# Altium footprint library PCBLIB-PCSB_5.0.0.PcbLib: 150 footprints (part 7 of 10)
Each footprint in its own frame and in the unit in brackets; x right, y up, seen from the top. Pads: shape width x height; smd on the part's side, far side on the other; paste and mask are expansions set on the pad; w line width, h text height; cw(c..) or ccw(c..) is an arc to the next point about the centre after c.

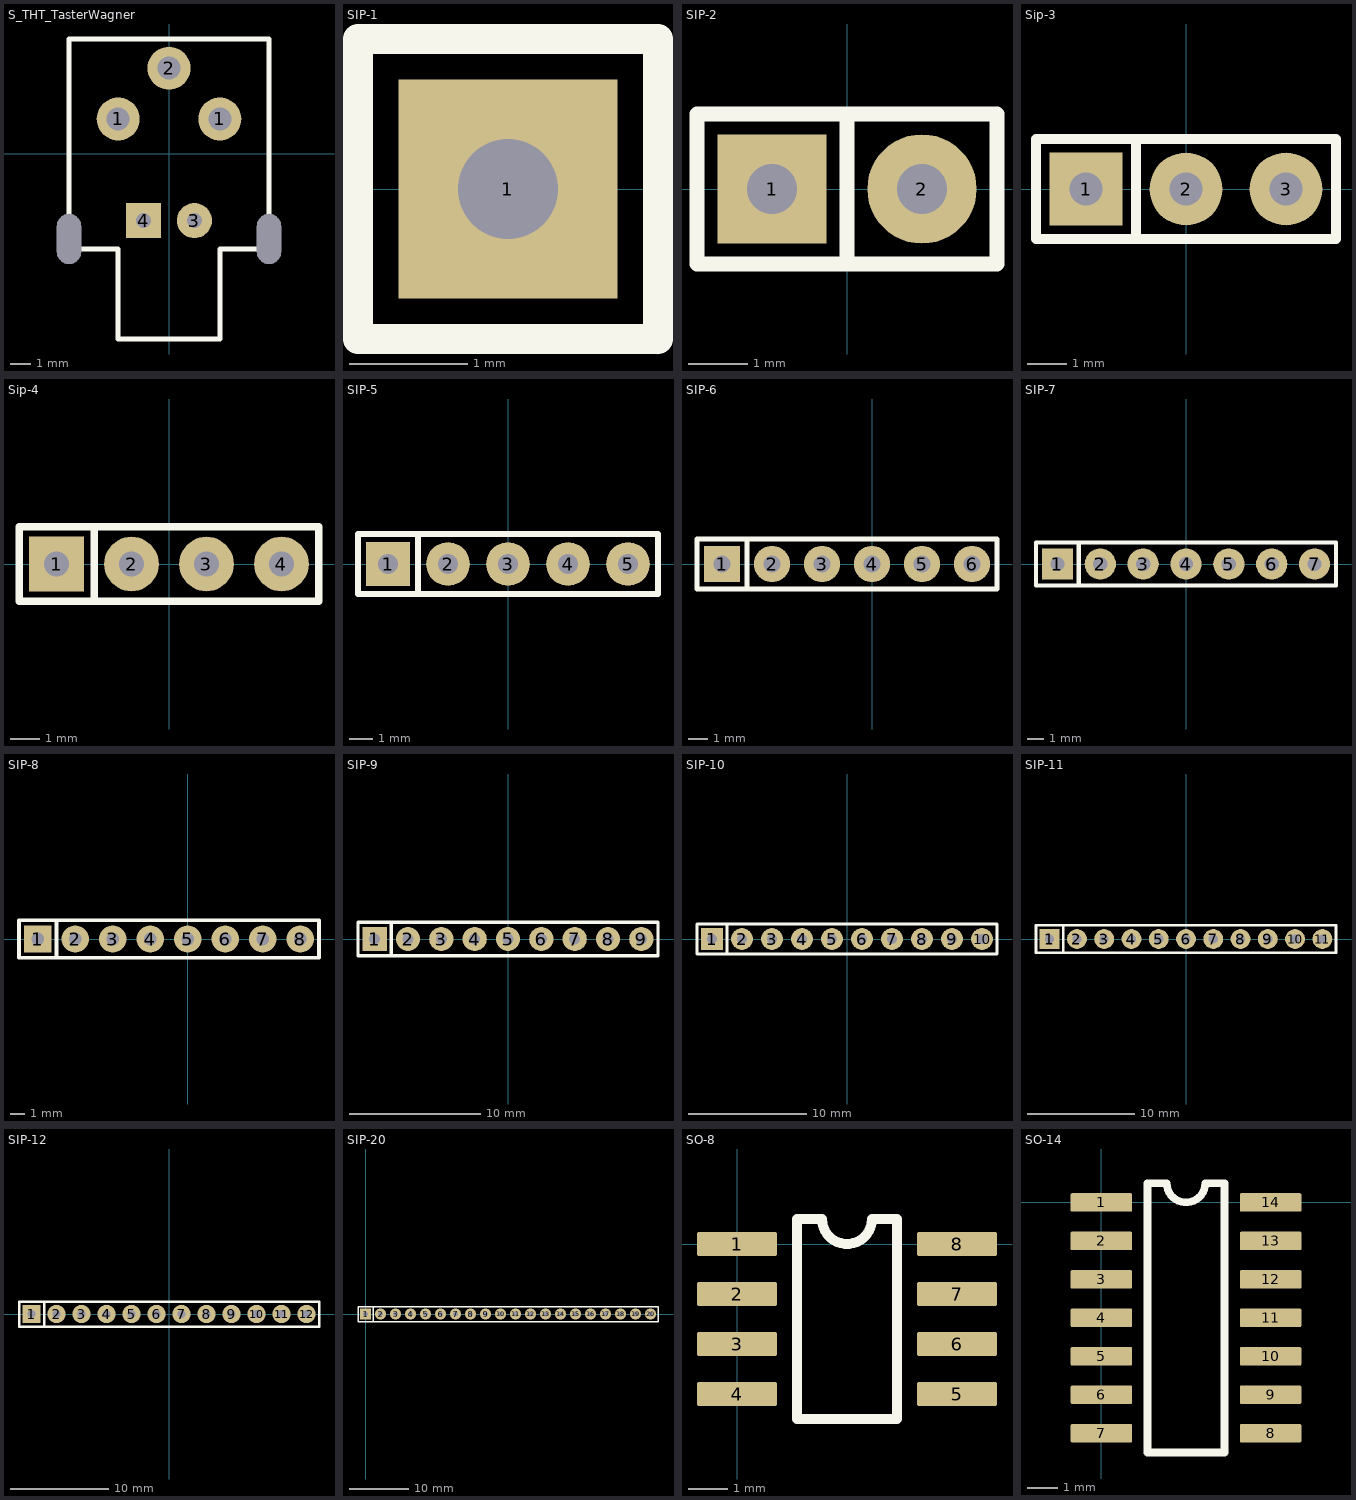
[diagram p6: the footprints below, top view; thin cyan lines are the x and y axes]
## S_THT_TasterWagner [mm] "LB-2024-04-17"
pads (7):
  round 2.15 hole 1.15: 1(-2.54,1.73) 1(2.54,1.73) 2(0,4.27)
  round 1.75 hole 0.75: 3(1.27,-3.35)
  rect 1.75x1.75 hole 0.75: 4(-1.27,-3.35)
  round 0.1 hole 1.2 slot 2.5 at 90 deg: H1(-5,-4.27) H2(5,-4.27)
Top Overlay:
  lines w0.254: -5,-4.77 -2.54,-4.77 -2.54,-9.27 1.065,-9.27 2.54,-9.27 2.54,-4.77 5,-4.77 5,5.73 -5,5.73 -5,-4.77

## SIP-1 [mm] "LB-2024-04-17"
pads (1):
  rect 1.85x1.85 hole 0.85: 1(-1.27,0)
Top Overlay:
  lines w0.254: -2.54,-1.27 0,-1.27 0,1.27 -2.54,1.27 -2.54,-1.27

## SIP-2 [mm] "LB-2024-04-17"
pads (2):
  rect 1.85x1.85 hole 0.85: 1(-1.27,0)
  round 1.85 hole 0.85: 2(1.27,0)
Top Overlay:
  lines w0.254: 0,-1.27 0,1.27 ; -2.54,-1.27 2.54,-1.27 2.54,1.27 -2.54,1.27 -2.54,-1.27

## Sip-3 [mm] "LB-2024-04-17"
pads (3):
  rect 1.85x1.85 hole 0.85: 1(-2.54,0)
  round 1.85 hole 0.85: 2(0,0) 3(2.54,0)
Top Overlay:
  lines w0.254: -1.27,-1.27 -1.27,1.27 ; -3.81,-1.27 -3.81,1.27 3.81,1.27 3.81,-1.27 -3.81,-1.27

## Sip-4 [mm] "LB-2024-04-17"
pads (4):
  rect 1.85x1.85 hole 0.85: 1(-3.81,0)
  round 1.85 hole 0.85: 2(-1.27,0) 3(1.27,0) 4(3.81,0)
Top Overlay:
  lines w0.254: -2.54,-1.27 -2.54,1.27 ; -5.08,-1.27 5.08,-1.27 5.08,1.27 -5.08,1.27 -5.08,-1.27

## SIP-5 [mm] "LB-2024-04-17"
pads (5):
  rect 1.85x1.85 hole 0.85: 1(-5.08,0)
  round 1.85 hole 0.85: 2(-2.54,0) 3(0,0) 4(2.54,0) 5(5.08,0)
Top Overlay:
  lines w0.254: -3.81,-1.27 -3.81,1.27 ; -6.35,-1.27 6.35,-1.27 6.35,1.27 -6.35,1.27 -6.35,-1.27

## SIP-6 [mm] "LB-2024-04-17"
pads (6):
  rect 1.85x1.85 hole 0.85: 1(-7.62,0)
  round 1.85 hole 0.85: 2(-5.08,0) 3(-2.54,0) 4(0,0) 5(2.54,0) 6(5.08,0)
Top Overlay:
  lines w0.254: -6.35,-1.27 -6.35,1.27 ; -8.89,-1.27 -8.89,1.27 6.35,1.27 6.35,-1.27 -8.89,-1.27

## SIP-7 [mm] "LB-2024-04-17"
pads (7):
  rect 1.85x1.85 hole 0.85: 1(-7.62,0)
  round 1.85 hole 0.85: 2(-5.08,0) 3(-2.54,0) 4(0,0) 5(2.54,0) 6(5.08,0) 7(7.62,0)
Top Overlay:
  lines w0.254: -6.35,-1.27 -6.35,1.27 ; -8.89,-1.27 8.89,-1.27 8.89,1.27 -8.89,1.27 -8.89,-1.27

## SIP-8 [mm] "LB-2024-04-17"
pads (8):
  rect 1.85x1.85 hole 0.85: 1(-10.16,0)
  round 1.85 hole 0.85: 2(-7.62,0) 3(-5.08,0) 4(-2.54,0) 5(0,0) 6(2.54,0) 7(5.08,0) 8(7.62,0)
Top Overlay:
  lines w0.254: -8.89,-1.27 -8.89,1.27 ; -11.43,-1.27 -11.43,1.27 8.89,1.27 8.89,-1.27 -11.43,-1.27

## SIP-9 [mm] "LB-2024-04-17"
pads (9):
  rect 1.85x1.85 hole 0.85: 1(-10.16,0)
  round 1.85 hole 0.85: 2(-7.62,0) 3(-5.08,0) 4(-2.54,0) 5(0,0) 6(2.54,0) 7(5.08,0) 8(7.62,0) 9(10.16,0)
Top Overlay:
  lines w0.254: -8.89,-1.27 -8.89,1.27 ; -11.43,-1.27 11.43,-1.27 11.43,1.27 -11.43,1.27 -11.43,-1.27

## SIP-10 [mm] "LB-2024-04-17"
pads (10):
  rect 1.85x1.85 hole 0.85: 1(-11.43,0)
  round 1.85 hole 0.85: 2(-8.89,0) 3(-6.35,0) 4(-3.81,0) 5(-1.27,0) 6(1.27,0) 7(3.81,0) 8(6.35,0) 9(8.89,0) 10(11.43,0)
Top Overlay:
  lines w0.254: -10.16,-1.27 -10.16,1.27 ; -12.7,-1.27 12.7,-1.27 12.7,1.27 -12.7,1.27 -12.7,-1.27

## SIP-11 [mm] "LB-2024-04-17"
pads (11):
  rect 1.85x1.85 hole 0.85: 1(-12.7,0)
  round 1.85 hole 0.85: 2(-10.16,0) 3(-7.62,0) 4(-5.08,0) 5(-2.54,0) 6(0,0) 7(2.54,0) 8(5.08,0) 9(7.62,0) 10(10.16,0) 11(12.7,0)
Top Overlay:
  lines w0.254: -11.43,-1.27 -11.43,1.27 ; -13.97,-1.27 -13.97,1.27 13.97,1.27 13.97,-1.27 -13.97,-1.27

## SIP-12 [mm] "LB-2024-04-17"
pads (12):
  rect 1.85x1.85 hole 0.85: 1(-13.97,0)
  round 1.85 hole 0.85: 2(-11.43,0) 3(-8.89,0) 4(-6.35,0) 5(-3.81,0) 6(-1.27,0) 7(1.27,0) 8(3.81,0) 9(6.35,0) 10(8.89,0) 11(11.43,0) 12(13.97,0)
Top Overlay:
  lines w0.254: -12.7,-1.27 -12.7,1.27 ; -15.24,-1.27 -15.24,1.27 15.24,1.27 15.24,-1.27 -15.24,-1.27

## SIP-20 [mm] "LB-2024-04-17"
pads (20):
  rect 1.85x1.85 hole 0.85: 1(0,0)
  round 1.85 hole 0.85: 2(2.54,0) 3(5.08,0) 4(7.62,0) 5(10.16,0) 6(12.7,0) 7(15.24,0) 8(17.78,0) 9(20.32,0) 10(22.86,0) 11(25.4,0) 12(27.94,0) 13(30.48,0) 14(33.02,0) 15(35.56,0) 16(38.1,0) 17(40.64,0) 18(43.18,0) 19(45.72,0) 20(48.26,0)
Top Overlay:
  lines w0.254: 1.27,-1.27 1.27,1.27 ; -1.27,-1.27 -1.27,1.27 49.53,1.27 49.53,-1.27 -1.27,-1.27

## SO-8 [mil] "LB-2024-04-17"
pads (8):
  rrect15% 80x24 smd paste-0.79 mask+1.97: 1(0,0) 2(0,-50) 3(0,-100) 4(0,-150) 5(220,-150) 6(220,-100) 7(220,-50) 8(220,0)
Top Overlay:
  lines w10: 60,-175 160,-175 160,25 135,25 cw(c110,25) 85,25 60,25 60,-175

## SO-14 [mil] "LB-2024-04-17"
pads (14):
  rrect15% 80x24 smd paste-0.79 mask+1.97: 1(0,0) 2(0,-50) 3(0,-100) 4(0,-150) 5(0,-200) 6(0,-250) 7(0,-300) 8(220,-300) 9(220,-250) 10(220,-200) 11(220,-150) 12(220,-100) 13(220,-50) 14(220,0)
Top Overlay:
  lines w10: 60,-325 160,-325 160,25 135,25 cw(c110,25) 85,25 60,25 60,-325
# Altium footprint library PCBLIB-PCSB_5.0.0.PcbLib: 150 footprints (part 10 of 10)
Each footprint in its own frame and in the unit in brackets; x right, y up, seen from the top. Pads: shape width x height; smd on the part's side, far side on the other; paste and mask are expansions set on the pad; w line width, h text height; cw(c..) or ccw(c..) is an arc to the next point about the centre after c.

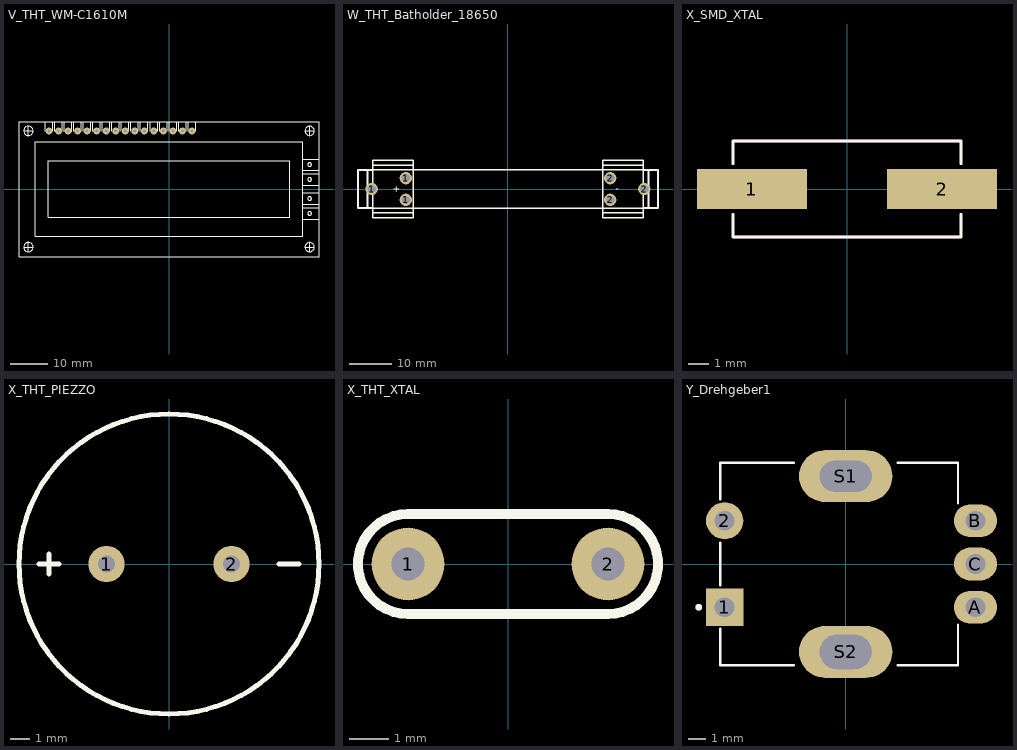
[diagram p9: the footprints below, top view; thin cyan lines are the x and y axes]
## V_THT_WM-C1610M [mm] "LB-2024-04-19"
pads (16):
  round 1.85 hole 0.85: 1(-32,15.5) 2(-29.46,15.5) 3(-26.92,15.5) 4(-24.38,15.5) 5(-21.84,15.5) 6(-19.3,15.5) 7(-16.76,15.5) 8(-14.22,15.5) 9(-11.68,15.5) 10(-9.14,15.5) 11(-6.6,15.5) 12(-4.06,15.5) 13(-1.52,15.5) 14(1.02,15.5) 15(3.56,15.5) 16(6.1,15.5)
Top Overlay:
  circle w0.2: c-37.51,15.538 r1.25
  circle w0.2: c-37.51,-15.462 r1.25
  circle w0.2: c37.49,15.538 r1.25
  circle w0.2: c37.49,6.538 r0.5
  circle w0.2: c37.49,2.578 r0.5
  circle w0.2: c37.49,-2.502 r0.5
  circle w0.2: c37.49,-6.462 r0.5
  circle w0.2: c37.49,-15.462 r1.25
  lines w0.1: -38.75,-15.462 -36.26,-15.462 ; -38.75,15.538 -36.26,15.538 ; -37.51,-16.75 -37.51,-14.25 ; -37.51,14.25 -37.51,16.75 ; 36.25,-15.462 38.74,-15.462 ; 36.25,15.538 38.74,15.538 ; 37.49,-16.75 37.49,-14.25 ; 37.49,14.25 37.49,16.75
  lines w0.2: -33.01,15.498 -33.01,18.038 ; -31.01,15.498 -31.01,18.038 ; -30.47,15.498 -30.47,18.038 ; -28.47,15.498 -28.47,18.038 ; -27.93,15.338 -27.93,18.038 ; -25.93,15.338 -25.93,18.038 ; -25.39,15.498 -25.39,18.038 ; -23.39,15.498 -23.39,18.038 ; -22.85,15.498 -22.85,18.038 ; -20.85,15.498 -20.85,18.038 ; -20.31,15.498 -20.31,18.038 ; -18.31,15.498 -18.31,18.038 ; -17.77,15.498 -17.77,18.038 ; -15.77,15.498 -15.77,18.038 ; -15.23,15.498 -15.23,18.038 ; -13.23,15.498 -13.23,18.038 ; -12.69,15.498 -12.69,18.038 ; -10.69,15.498 -10.69,18.038 ; -10.15,15.468 -10.15,18.038 ; -8.15,15.468 -8.15,18.038 ; -7.61,15.468 -7.61,18.038 ; -5.61,15.468 -5.61,18.038 ; -5.07,15.498 -5.07,18.038 ; -3.07,15.498 -3.07,18.038 ; -2.53,15.498 -2.53,18.038 ; -0.53,15.498 -0.53,18.038 ; 0.01,15.498 0.01,18.038 ; 2.01,15.498 2.01,18.038 ; 2.55,15.498 2.55,18.038 ; 4.55,15.498 4.55,18.038 ; 5.09,15.498 5.09,18.038 ; 7.09,15.498 7.09,18.038 ; 35.59,-7.962 39.99,-7.962 ; 35.59,-4.962 39.99,-4.962 ; 35.59,-4.002 39.99,-4.002 ; 35.59,-1.002 39.99,-1.002 ; 35.59,1.078 39.99,1.078 ; 35.59,4.078 39.99,4.078 ; 35.59,5.038 39.99,5.038 ; 35.59,8.038 39.99,8.038 ; -40.01,-17.962 39.99,-17.962 39.99,18.038 -40.01,18.038 -40.01,-17.962 ; -35.61,-12.562 -35.61,12.638 35.59,12.638 35.59,-12.562 -35.61,-12.562 ; -32.24,-7.462 32.22,-7.462 32.22,7.538 -32.24,7.538 -32.24,-7.462

## W_THT_Batholder_18650 [mm] "LB-2024-04-25"
height 17
pads (6):
  round 2.9 hole 1.9: 1(-32,0) 1(-24,-2.54) 1(-24,2.54) 2(24.006,-2.54) 2(24.006,2.54) 2(32,0)
Top Overlay:
  lines w0.4: -31.74,-6.75 -22.27,-6.75 ; -31.74,-6.71 -31.74,-5.552 -29.08,-5.552 -22.272,-5.552 ; -31.74,-5.492 -31.74,5.552 ; -31.74,-4.45 -35.22,-4.45 -35.22,4.45 -31.74,4.45 ; -31.74,6.71 -31.74,5.552 ; -31.74,6.75 -22.27,6.75 ; -22.272,5.552 -29.08,5.552 -31.74,5.552 ; -22.22,-6.75 -22.22,-5.552 -22.22,5.552 -22.22,6.75 ; 22.226,-6.75 22.226,-5.552 22.226,5.552 22.226,6.75 ; 22.276,-6.75 31.746,-6.75 ; 22.276,6.75 31.746,6.75 ; 22.278,-5.552 29.086,-5.552 31.746,-5.552 ; 22.278,5.552 29.086,5.552 31.746,5.552 31.746,6.71 ; 31.746,-6.71 31.746,-5.552 ; 31.746,-4.45 35.226,-4.45 35.226,4.45 31.746,4.45 ; 31.746,5.492 31.746,-5.552 ; -33,-4.5 33,-4.5 33,0 33,4.5 -33,4.5 -33,0 -33,-4.5
  text "+" at -25.3,0.7 h1.52
  text "-" at 25.3,-0.7 h1.52

## X_SMD_XTAL [mm] "LB-2024-04-17"
pads (2):
  rect 5.5x2 smd: 1(-4.75,0) 2(4.75,0)
Top Overlay:
  lines w0.127: -5.7,-1.254 -5.7,-2.4 5.7,-2.4 5.7,-1.254 ; -5.7,1.254 -5.7,2.4 5.7,2.4 5.7,1.254
Mechanical 13:
  lines w0.127: -5.7,-2.4 5.7,-2.4 ; -5.7,2.4 5.7,2.4

## X_THT_PIEZZO [mm] "LB-2024-04-18"
pads (2):
  round 1.85 hole 0.85: 1(-3.175,0) 2(3.175,0)
Top Overlay:
  circle w0.254: c0,0 r7.62
  lines w0.254: -6.604,0 -5.588,0 ; -6.096,-0.508 -6.096,0.508 ; 5.588,0 6.604,0

## X_THT_XTAL [mm] "LB-2024-04-17"
pads (2):
  round 1.85 hole 0.85: 1(-2.54,0) 2(2.54,0)
Top Overlay:
  lines w0.254: -2.54,-1.27 cw(c-2.54,0) -2.54,1.27 2.54,1.27 cw(c2.54,0) 2.54,-1.27 -2.54,-1.27

## Y_Drehgeber1 [mm] "LB-2024-04-19"
pads (7):
  rect 2.15x2.15 hole 1.15: 1(-7,-2.5)
  round 2.15 hole 1.15: 2(-7,2.5)
  oval 2.5x1.9 hole 1.15: A(7.5,-2.5) B(7.5,2.5) C(7.5,0)
  oval 5.4x3 hole 1.8 slot 3 at 0 deg: S1(0,5.08)
  oval 5.4x3 hole 2 slot 3 at 0 deg: S2(0,-5.08)
Top Overlay:
  circle w0.2: c-8.5,-2.5 r0.1
  lines w0.127: -7.25,-3.75 -7.25,-5.85 -3,-5.85 ; -7.25,-1.25 -7.25,1.25 ; -7.25,3.75 -7.25,5.85 -3,5.85 ; 3,-5.85 6.5,-5.85 6.5,-3.5 ; 3,5.85 6.5,5.85 6.5,3.5
Mechanical 13:
  circle w0.2: c-8.5,-2.5 r0.1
